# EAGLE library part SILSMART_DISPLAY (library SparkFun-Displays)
14-Segment Alphanumeric LED Display from Silsmart Optoelectronics

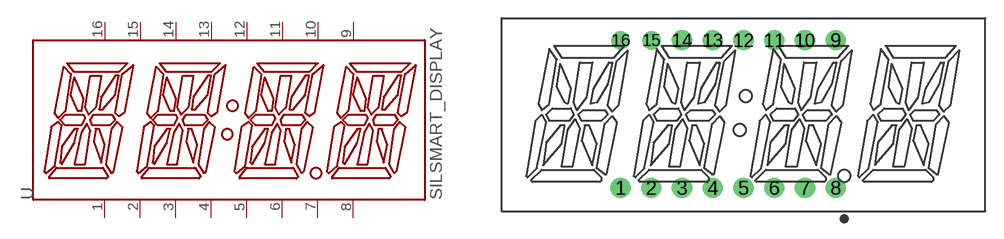
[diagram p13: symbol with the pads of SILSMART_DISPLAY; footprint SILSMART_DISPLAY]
Designator prefix U

## SILSMART_DISPLAY-PINK (PROD_ID: COMP-15045; VALUE: Alphanumeric Display)  [SILSMART_DISPLAY]
1  DIG_1B
2  DIG_2B
3  COM_D
4  COM_C
5  COM_G1
6  COM_E
7  DIG_DP
8  DIG_4A
9  DIG_4B
10  DIG_3B
11  DIG_3A
12  COM_F
13  COM_B
14  COM_A
15  DIG_2A
16  DIG_1A

## Footprint SILSMART_DISPLAY (pad centres in mm)
drill 0.75 pad 1.676: 1 -10.178,-6.092; 2 -7.638,-6.092; 3 -5.098,-6.092; 4 -2.558,-6.092; 5 -0.018,-6.092; 6 2.522,-6.092; 7 5.062,-6.092; 8 7.602,-6.092; 9 7.602,6.148; 10 5.062,6.148; 11 2.522,6.148; 12 -0.018,6.148; 13 -2.558,6.148; 14 -5.098,6.148
drill 0.75 pad 1.524: 15 -7.638,6.148; 16 -10.178,6.148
